VERSION 5.7 ;
  NOWIREEXTENSIONATPIN ON ;
  DIVIDERCHAR "/" ;
  BUSBITCHARS "[]" ;
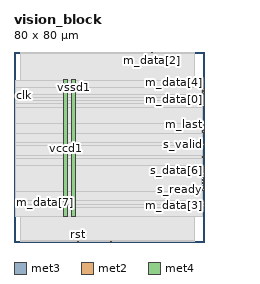
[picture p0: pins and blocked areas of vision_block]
MACRO vision_block
  CLASS BLOCK ;
  FOREIGN vision_block ;
  ORIGIN 0.000 0.000 ;
  SIZE 80.000 BY 80.000 ;
  PIN clk
    DIRECTION INPUT ;
    USE SIGNAL ;
    ANTENNAGATEAREA 1.286700 ;
    ANTENNADIFFAREA 0.434700 ;
    PORT
      LAYER met3 ;
        RECT 0.000 61.240 0.600 61.840 ;
    END
  END clk
  PIN m_data[0]
    DIRECTION OUTPUT ;
    USE SIGNAL ;
    ANTENNADIFFAREA 0.795200 ;
    PORT
      LAYER met3 ;
        RECT 79.400 59.880 80.000 60.480 ;
    END
  END m_data[0]
  PIN m_data[1]
    DIRECTION OUTPUT ;
    USE SIGNAL ;
    ANTENNADIFFAREA 0.795200 ;
    PORT
      LAYER met3 ;
        RECT 79.400 57.160 80.000 57.760 ;
    END
  END m_data[1]
  PIN m_data[2]
    DIRECTION OUTPUT ;
    USE SIGNAL ;
    ANTENNADIFFAREA 0.795200 ;
    PORT
      LAYER met2 ;
        RECT 58.050 79.720 58.330 80.000 ;
    END
  END m_data[2]
  PIN m_data[3]
    DIRECTION OUTPUT ;
    USE SIGNAL ;
    PORT
      LAYER met3 ;
        RECT 79.400 15.000 80.000 15.600 ;
    END
  END m_data[3]
  PIN m_data[4]
    DIRECTION OUTPUT ;
    USE SIGNAL ;
    PORT
      LAYER met3 ;
        RECT 79.400 63.960 80.000 64.560 ;
    END
  END m_data[4]
  PIN m_data[5]
    DIRECTION OUTPUT ;
    USE SIGNAL ;
    PORT
      LAYER met3 ;
        RECT 79.400 62.600 80.000 63.200 ;
    END
  END m_data[5]
  PIN m_data[6]
    DIRECTION OUTPUT ;
    USE SIGNAL ;
    PORT
      LAYER met3 ;
        RECT 79.400 16.360 80.000 16.960 ;
    END
  END m_data[6]
  PIN m_data[7]
    DIRECTION OUTPUT ;
    USE SIGNAL ;
    PORT
      LAYER met3 ;
        RECT 0.000 16.360 0.600 16.960 ;
    END
  END m_data[7]
  PIN m_last
    DIRECTION OUTPUT ;
    USE SIGNAL ;
    ANTENNADIFFAREA 0.795200 ;
    PORT
      LAYER met3 ;
        RECT 79.400 46.280 80.000 46.880 ;
    END
  END m_last
  PIN m_ready
    DIRECTION INPUT ;
    USE SIGNAL ;
    ANTENNAGATEAREA 0.647700 ;
    ANTENNADIFFAREA 0.434700 ;
    PORT
      LAYER met3 ;
        RECT 79.400 47.640 80.000 48.240 ;
    END
  END m_ready
  PIN m_valid
    DIRECTION OUTPUT ;
    USE SIGNAL ;
    ANTENNADIFFAREA 0.795200 ;
    PORT
      LAYER met3 ;
        RECT 79.400 49.000 80.000 49.600 ;
    END
  END m_valid
  PIN rst
    DIRECTION INPUT ;
    USE SIGNAL ;
    ANTENNAGATEAREA 0.647700 ;
    ANTENNADIFFAREA 0.434700 ;
    PORT
      LAYER met2 ;
        RECT 26.770 0.000 27.050 0.280 ;
    END
  END rst
  PIN s_data[0]
    DIRECTION INPUT ;
    USE SIGNAL ;
    ANTENNAGATEAREA 0.647700 ;
    ANTENNADIFFAREA 0.434700 ;
    PORT
      LAYER met2 ;
        RECT 40.570 0.000 40.850 0.280 ;
    END
  END s_data[0]
  PIN s_data[1]
    DIRECTION INPUT ;
    USE SIGNAL ;
    ANTENNAGATEAREA 0.647700 ;
    ANTENNADIFFAREA 0.434700 ;
    PORT
      LAYER met3 ;
        RECT 79.400 31.320 80.000 31.920 ;
    END
  END s_data[1]
  PIN s_data[2]
    DIRECTION INPUT ;
    USE SIGNAL ;
    ANTENNAGATEAREA 0.647700 ;
    ANTENNADIFFAREA 0.434700 ;
    PORT
      LAYER met3 ;
        RECT 79.400 24.520 80.000 25.120 ;
    END
  END s_data[2]
  PIN s_data[3]
    DIRECTION INPUT ;
    USE SIGNAL ;
    ANTENNAGATEAREA 0.647700 ;
    ANTENNADIFFAREA 0.434700 ;
    PORT
      LAYER met3 ;
        RECT 79.400 25.880 80.000 26.480 ;
    END
  END s_data[3]
  PIN s_data[4]
    DIRECTION INPUT ;
    USE SIGNAL ;
    ANTENNAGATEAREA 0.647700 ;
    ANTENNADIFFAREA 0.434700 ;
    PORT
      LAYER met3 ;
        RECT 79.400 23.160 80.000 23.760 ;
    END
  END s_data[4]
  PIN s_data[5]
    DIRECTION INPUT ;
    USE SIGNAL ;
    ANTENNAGATEAREA 0.647700 ;
    ANTENNADIFFAREA 0.434700 ;
    PORT
      LAYER met3 ;
        RECT 79.400 27.240 80.000 27.840 ;
    END
  END s_data[5]
  PIN s_data[6]
    DIRECTION INPUT ;
    USE SIGNAL ;
    ANTENNAGATEAREA 0.647700 ;
    ANTENNADIFFAREA 0.434700 ;
    PORT
      LAYER met3 ;
        RECT 79.400 29.960 80.000 30.560 ;
    END
  END s_data[6]
  PIN s_data[7]
    DIRECTION INPUT ;
    USE SIGNAL ;
    ANTENNAGATEAREA 0.647700 ;
    ANTENNADIFFAREA 0.434700 ;
    PORT
      LAYER met3 ;
        RECT 79.400 28.600 80.000 29.200 ;
    END
  END s_data[7]
  PIN s_last
    DIRECTION INPUT ;
    USE SIGNAL ;
    ANTENNAGATEAREA 0.647700 ;
    ANTENNADIFFAREA 0.434700 ;
    PORT
      LAYER met3 ;
        RECT 79.400 35.400 80.000 36.000 ;
    END
  END s_last
  PIN s_ready
    DIRECTION OUTPUT ;
    USE SIGNAL ;
    ANTENNADIFFAREA 0.795200 ;
    PORT
      LAYER met3 ;
        RECT 79.400 21.800 80.000 22.400 ;
    END
  END s_ready
  PIN s_valid
    DIRECTION INPUT ;
    USE SIGNAL ;
    ANTENNAGATEAREA 0.647700 ;
    ANTENNADIFFAREA 0.434700 ;
    PORT
      LAYER met3 ;
        RECT 79.400 40.840 80.000 41.440 ;
    END
  END s_valid
  PIN vccd1
    DIRECTION INOUT ;
    USE POWER ;
    PORT
      LAYER met4 ;
        RECT 21.040 10.640 22.640 68.240 ;
    END
  END vccd1
  PIN vssd1
    DIRECTION INOUT ;
    USE GROUND ;
    PORT
      LAYER met4 ;
        RECT 24.340 10.640 25.940 68.240 ;
    END
  END vssd1
  OBS
      LAYER nwell ;
        RECT 5.330 10.795 74.250 68.190 ;
      LAYER li1 ;
        RECT 5.520 10.795 74.060 68.085 ;
      LAYER met1 ;
        RECT 2.830 10.640 75.830 68.240 ;
      LAYER met2 ;
        RECT 2.850 79.440 57.770 79.720 ;
        RECT 58.610 79.440 75.810 79.720 ;
        RECT 2.850 0.560 75.810 79.440 ;
        RECT 2.850 0.280 26.490 0.560 ;
        RECT 27.330 0.280 40.290 0.560 ;
        RECT 41.130 0.280 75.810 0.560 ;
      LAYER met3 ;
        RECT 0.600 64.960 79.400 68.165 ;
        RECT 0.600 62.240 79.000 64.960 ;
        RECT 1.000 62.200 79.000 62.240 ;
        RECT 1.000 60.880 79.400 62.200 ;
        RECT 1.000 60.840 79.000 60.880 ;
        RECT 0.600 59.480 79.000 60.840 ;
        RECT 0.600 58.160 79.400 59.480 ;
        RECT 0.600 56.760 79.000 58.160 ;
        RECT 0.600 50.000 79.400 56.760 ;
        RECT 0.600 45.880 79.000 50.000 ;
        RECT 0.600 41.840 79.400 45.880 ;
        RECT 0.600 40.440 79.000 41.840 ;
        RECT 0.600 36.400 79.400 40.440 ;
        RECT 0.600 35.000 79.000 36.400 ;
        RECT 0.600 32.320 79.400 35.000 ;
        RECT 0.600 21.400 79.000 32.320 ;
        RECT 0.600 17.360 79.400 21.400 ;
        RECT 1.000 15.960 79.000 17.360 ;
        RECT 0.600 14.600 79.000 15.960 ;
        RECT 0.600 10.715 79.400 14.600 ;
  END
END vision_block
END LIBRARY

